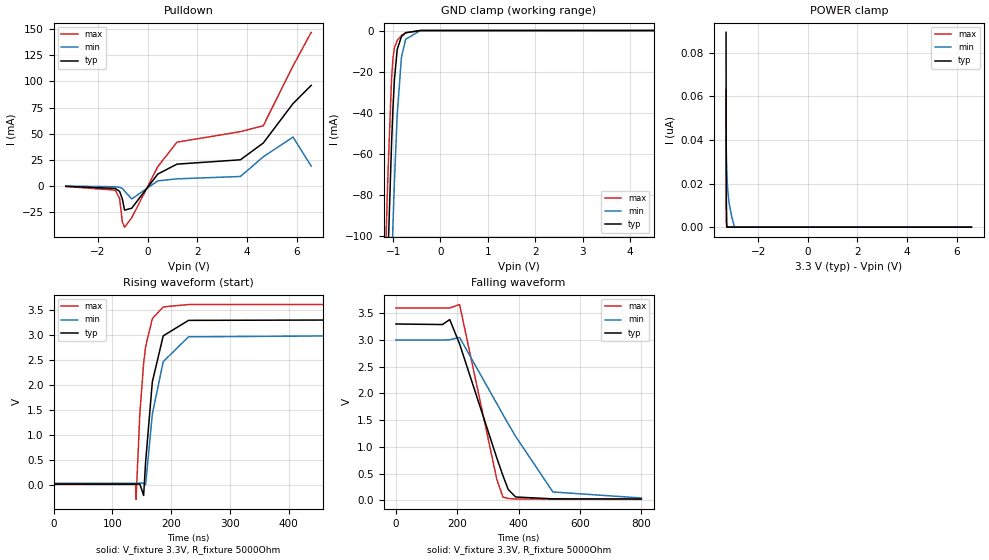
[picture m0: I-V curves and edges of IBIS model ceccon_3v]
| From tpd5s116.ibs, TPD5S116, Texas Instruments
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[Model]   ceccon_3v
Model_type   I/O_open_drain
Polarity   Non-Inverting
Enable   Active-Low
Vinl = .9
Vinh = 2.52
Vmeas = 1.65
Vref = 3.3
Cref = 15pF
Rref = 5000
|   typ   min   max
|   (nom PVT)   (slow PVT)   (fast PVT)
C_comp   0.9944p   0.9335p   1.0791p
| Where nom  PVT is Nominal Process, 3.3V, 27C
|   Fast PVT is Strong Process,  3.6V, -40C
|   Slow PVT is Weak Process,   3.0V, 125C
[Voltage Range]   3.3   3   3.6
[Temperature Range]   27   125   -40
[Pullup Reference]   3.3   3   3.6
[Pulldown Reference]   -0   -0   -0
[Power Clamp Reference]   3.3   3   3.6
[GND Clamp Reference]   -0   -0   -0
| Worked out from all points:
|   slope of the pulldown table from 0 to 0.495 V, typ, clamps not added: 37 ohm
|   GND clamp passes 1 mA (typ) near -0.73 V on its own axis
|   falling waveform, V_fixture 3.3V, R_fixture 5000Ohm: 20-80 % time 112ns typ, 177ns min, 78.7ns max; typ from 3.3 V to 0.024 V
|   rising waveform, V_fixture 3.3V, R_fixture 5000Ohm: 20-80 % time 19.2ns typ, 23.8ns min, 14.4ns max; typ from 0.024 V to 3.3 V
[Pulldown]
|   Voltage   I(typ)   I(min)   I(max)
-3.29V    -264.8uA   -78.16uA   -395.9uA
-1.3V     -2.289mA   -661.8uA   -3.952mA
-1.122V   -5.204mA   -1.276mA   -12.04mA
-1.013V   -12.49mA   -2.369mA   -34.54mA
-924mV    -23.06mA   -4.74mA    -39.32mA
-636.9mV  -21.2mA    -12.36mA   -30.39mA
412.5mV   11.45mA    4.92mA     18.48mA
1.185V    20.94mA    6.875mA    41.96mA
3.739V    25.11mA    9.143mA    51.98mA
4.66V     41.17mA    27.98mA    57.62mA
5.857V    78.84mA    46.85mA    114.9mA
6.59V     96.28mA    19mA       147mA
[GND Clamp]
|   Voltage   I(typ)   I(min)   I(max)
-3.29V    -2.207A    -2.262A    -2.175A
-1.211V   -195mA     -262.1mA   -153.1mA
-1.152V   -144.3mA   -211mA     -102.8mA
-1.112V   -112.1mA   -177.9mA   -71.76mA
-1.033V   -54.92mA   -115.6mA   -23.29mA
-1.003V   -37.74mA   -94.21mA   -13.55mA
-973.5mV  -24.2mA    -74.32mA   -8.55mA
-914.1mV  -9.265mA   -41.02mA   -4.823mA
-825mV    -2.968mA   -13.13mA   -2.43mA
-735.9mV  -1.1mA     -4.271mA   -1.07mA
-429mV    -4.808uA   -22.23uA   -1.788uA
6.59V     0A         0A         0A
[POWER Clamp]
|   Voltage   I(typ)   I(min)   I(max)
-3.29V    89.28nA    41.72nA    63.14nA
-3.28V    12.91nA    34.6nA     2.506nA
-3.27V    6.457nA    29.57nA    1.253nA
-3.26V    0A         25.83nA    0A
-3.241V   0A         20.58nA    0A
-3.221V   0A         17.02nA    0A
-3.191V   0A         13.32nA    0A
-3.161V   0A         10.67nA    0A
-3.053V   0A         4.344nA    0A
-2.954V   0A         161.6pA    0A
-2.934V   0A         0A         0A
6.59V     0A         0A         0A
[Ramp]
R_load = 5000
|   typ   min   max
dV/dt_r   1.96559/1.89851e-08   1.7748/2.38264e-08   2.14933/1.43828e-08
dV/dt_f   1.96557/1.12449e-07   1.77431/1.77199e-07   2.14934/7.86086e-08
[Falling Waveform]
V_fixture = 3.3V
V_fixture_min = 3V
V_fixture_max = 3.6V
R_fixture = 5000Ohm
C_fixture = 0F
|   Time   V(typ)   V(min)   V(max)
0s        3.3V       3V         3.6V
151.8ns   3.29V      3V         3.6V
175.4ns   3.383V     3.005V     3.6V
207.5ns   2.927V     3.049V     3.665V
329ns     789.4mV    1.808V     388mV
348.8ns   462.2mV    1.605V     59.01mV
366ns     202.3mV    1.431V     32.87mV
390.3ns   61.43mV    1.194V     24.86mV
511.7ns   26.79mV    155.9mV    20.48mV
800ns     24.04mV    42.66mV    17.77mV
[Rising Waveform]
V_fixture = 3.3V
V_fixture_min = 3V
V_fixture_max = 3.6V
R_fixture = 5000Ohm
C_fixture = 0F
|   Time   V(typ)   V(min)   V(max)
0s        24mV       41.94mV    17.76mV
139.5ns   24.91mV    42.78mV    18.77mV
140.3ns   24.92mV    42.78mV    -279.1mV
146.8ns   24.96mV    42.82mV    1.437V
153.2ns   -201.8mV   42.86mV    2.428V
156.6ns   469.7mV    14.03mV    2.762V
168ns     2.061V     1.42V      3.319V
186.5ns   2.976V     2.462V     3.552V
229.5ns   3.284V     2.956V     3.599V
800ns     3.3V       3V         3.6V
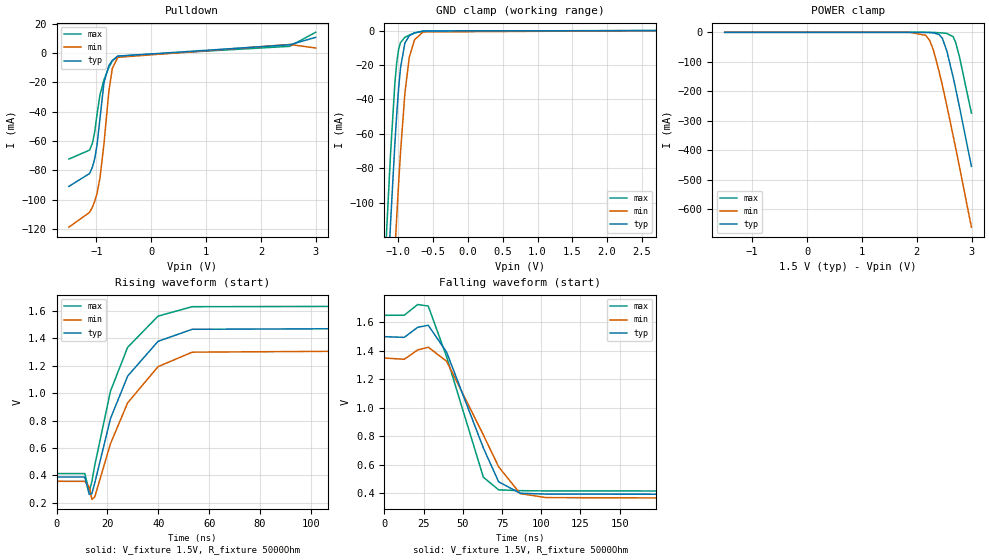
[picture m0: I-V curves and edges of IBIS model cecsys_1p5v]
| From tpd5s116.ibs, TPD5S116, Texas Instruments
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[Model]   cecsys_1p5v
Model_type   I/O_open_drain
Polarity   Non-Inverting
Enable   Active-Low
Vinl = .1107
Vinh = 1.155
Vmeas = 0.75
Vref = 1.5
Cref = 15pF
Rref = 5000
|   typ   min   max
|   (fast PVT)   (slow PVT)   (nom PVT)
C_comp   1.541p   0.9792p   1.562p
| Where nom  PVT is Nominal Process, 1.5V, 27C
|   Fast PVT is Strong Process,  1.65V, -40C
|   Slow PVT is Weak Process,   1.35V, 125C
[Voltage Range]   1.5   1.35   1.65
[Temperature Range]   27   125   -40
[Pullup Reference]   1.5   1.35   1.65
[Pulldown Reference]   -0   -0   -0
[Power Clamp Reference]   1.5   1.35   1.65
[GND Clamp Reference]   -0   -0   -0
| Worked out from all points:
|   slope of the pulldown table from 0 to 0.225 V, typ, clamps not added: 759 ohm
|   GND clamp passes 1 mA (typ) near -0.73 V on its own axis
|   falling waveform, V_fixture 1.5V, R_fixture 5000Ohm: 20-80 % time 23.3ns typ, 26ns min, 20ns max; typ from 1.5 V to 0.388 V
|   rising waveform, V_fixture 1.5V, R_fixture 5000Ohm: 20-80 % time 15.3ns typ, 17.2ns min, 13.4ns max; typ from 0.388 V to 1.5 V
[Pulldown]
|   Voltage   I(typ)   I(min)   I(max)
-1.5V     -90.99mA   -118.8mA   -72.32mA
-1.122V   -82.17mA   -108.7mA   -66.19mA
-1.068V   -77.53mA   -104.9mA   -61.14mA
-1.028V   -71.84mA   -101mA     -53.51mA
-987mV    -62.86mA   -95.73mA   -41.88mA
-933mV    -44.44mA   -85.2mA    -28.38mA
-861mV    -20.3mA    -62.12mA   -18.29mA
-771mV    -8.463mA   -26.03mA   -9.629mA
-708mV    -4.948mA   -10.38mA   -5.408mA
-609mV    -2.069mA   -2.867mA   -2.052mA
2.523V    5.706mA    5.906mA    4.641mA
2.995V    10.77mA    3.528mA    14.2mA
[GND Clamp]
|   Voltage   I(typ)   I(min)   I(max)
-1.5V     -459.6mA   -524.8mA   -419.6mA
-1.167V   -156.8mA   -223.6mA   -115.1mA
-1.113V   -112.4mA   -178.3mA   -71.92mA
-1.05V    -65.57mA   -128mA     -30.5mA
-1.023V   -48.2mA    -107.8mA   -18.38mA
-996mV    -33.32mA   -88.59mA   -10.82mA
-969mV    -21.62mA   -70.73mA   -6.986mA
-906mV    -7.277mA   -36.34mA   -3.927mA
-843mV    -3.002mA   -15.49mA   -2.631mA
-766.5mV  -1.313mA   -5.31mA    -1.448mA
-645mV    -325.3uA   -830.7uA   -306.8uA
2.995V    0A         0A         0A
[POWER Clamp]
|   Voltage   I(typ)   I(min)   I(max)
-1.5V     -130.4pA   -12.09nA   -7.081nA
1.875V    -1.27uA    -105.7uA   -20.84nA
2.163V    -415.8uA   -10.11mA   -18.49uA
2.235V    -955.3uA   -27.78mA   -97.14uA
2.303V    -1.894mA   -60.63mA   -347.8uA
2.406V    -7.277mA   -132.6mA   -1.311mA
2.465V    -20.02mA   -179.5mA   -2.153mA
2.546V    -62.53mA   -248.2mA   -3.671mA
2.663V    -153mA     -352.1mA   -14.91mA
2.708V    -191.6mA   -393.1mA   -34.61mA
2.775V    -251.4mA   -455.2mA   -81.1mA
2.995V    -455.3mA   -661.9mA   -274.3mA
[Ramp]
R_load = 5000
|   typ   min   max
dV/dt_r   0.665673/1.53219e-08   0.595776/1.71867e-08   0.740783/1.33653e-08
dV/dt_f   0.667299/2.32939e-08   0.595601/2.59501e-08   0.742096/1.99555e-08
[Falling Waveform]
V_fixture = 1.5V
V_fixture_min = 1.35V
V_fixture_max = 1.65V
R_fixture = 5000Ohm
C_fixture = 0F
|   Time   V(typ)   V(min)   V(max)
0s        1.5V       1.35V      1.65V
12.67ns   1.495V     1.341V     1.651V
21.2ns    1.566V     1.407V     1.726V
27.95ns   1.58V      1.426V     1.715V
39.65ns   1.391V     1.327V     1.358V
63.07ns   718mV      809.4mV    512.6mV
72.81ns   480.3mV    586.1mV    423.9mV
86.52ns   400.1mV    397.7mV    418.3mV
103.1ns   394.2mV    369.4mV    416.5mV
500ns     387.8mV    357.3mV    413.2mV
[Rising Waveform]
V_fixture = 1.5V
V_fixture_min = 1.35V
V_fixture_max = 1.65V
R_fixture = 5000Ohm
C_fixture = 0F
|   Time   V(typ)   V(min)   V(max)
0s        388.3mV    357.1mV    413.6mV
11.11ns   388.2mV    356.8mV    413.5mV
12.87ns   261mV      315.1mV    282mV
13.89ns   267.1mV    225.4mV    354.7mV
15.03ns   344.9mV    242.6mV    473.6mV
21.2ns    814mV      631mV      1.015V
27.95ns   1.125V     929.6mV    1.335V
39.9ns    1.379V     1.194V     1.563V
53.35ns   1.467V     1.3V       1.632V
500ns     1.498V     1.35V      1.648V
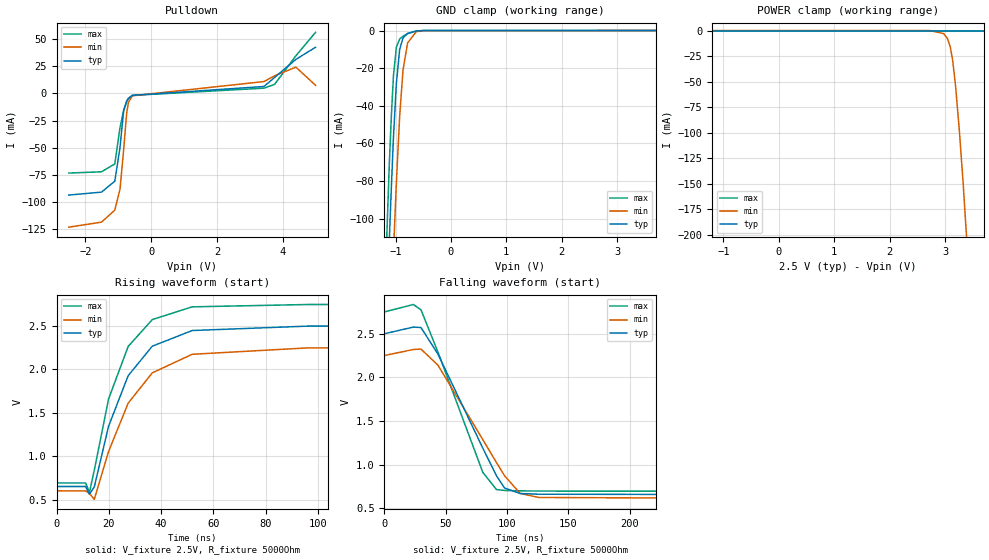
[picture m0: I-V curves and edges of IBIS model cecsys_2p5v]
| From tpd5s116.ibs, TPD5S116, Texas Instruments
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[Model]   cecsys_2p5v
Model_type   I/O_open_drain
Polarity   Non-Inverting
Enable   Active-Low
Vinl = .1845
Vinh = 1.925
Vmeas = 1.25
Vref = 2.5
Cref = 15pF
Rref = 5000
|   typ   min   max
|   (fast PVT)   (slow PVT)   (nom PVT)
C_comp   1.541p   0.9792p   1.562p
| Where nom  PVT is Nominal Process, 2.5V, 27C
|   Fast PVT is Strong Process,  2.75V, -40C
|   Slow PVT is Weak Process,   2.25V, 125C
[Voltage Range]   2.5   2.25   2.75
[Temperature Range]   27   125   -40
[Pullup Reference]   2.5   2.25   2.75
[Pulldown Reference]   -0   -0   -0
[Power Clamp Reference]   2.5   2.25   2.75
[GND Clamp Reference]   -0   -0   -0
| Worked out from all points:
|   slope of the pulldown table from 0 to 0.375 V, typ, clamps not added: 757 ohm
|   GND clamp passes 1 mA (typ) near -0.72 V on its own axis
|   falling waveform, V_fixture 2.5V, R_fixture 5000Ohm: 20-80 % time 37.6ns typ, 41.8ns min, 32.6ns max; typ from 2.5 V to 0.65 V
|   rising waveform, V_fixture 2.5V, R_fixture 5000Ohm: 20-80 % time 14.7ns typ, 16.5ns min, 13ns max; typ from 0.651 V to 2.5 V
[Pulldown]
|   Voltage   I(typ)   I(min)   I(max)
-2.5V     -93.77mA   -123.4mA   -73.47mA
-1.51V    -91.08mA   -118.8mA   -72.34mA
-1.105V   -80.99mA   -107.7mA   -65.06mA
-947.5mV  -50.03mA   -88.55mA   -31.49mA
-835mV    -15.38mA   -51.53mA   -15.7mA
-745mV    -6.991mA   -18.25mA   -7.913mA
-692.5mV  -4.506mA   -8.377mA   -4.856mA
-572.5mV  -1.775mA   -2.19mA    -1.818mA
3.425V    6.38mA     10.94mA    4.835mA
3.748V    14.76mA    16.28mA    8.39mA
4.393V    31.4mA     24.25mA    34.67mA
4.992V    42.57mA    7.465mA    56.37mA
[GND Clamp]
|   Voltage   I(typ)   I(min)   I(max)
-2.5V     -1.429A    -1.487A    -1.394A
-1.255V   -233.5mA   -300.5mA   -191.7mA
-1.113V   -112mA     -177.8mA   -71.55mA
-1.075V   -83.31mA   -147.5mA   -45.22mA
-1.038V   -57.27mA   -118.5mA   -24.34mA
-985mV    -28.13mA   -81.13mA   -8.909mA
-925mV    -9.995mA   -45.44mA   -4.484mA
-865mV    -3.982mA   -21.15mA   -3.033mA
-782.5mV  -1.541mA   -6.617mA   -1.669mA
-625mV    -242.5uA   -591.8uA   -215.1uA
-497.5mV  -22.76uA   -64.94uA   -12.46uA
4.992V    0A         0A         0A
[POWER Clamp]
|   Voltage   I(typ)   I(min)   I(max)
-2.5V     145.4pA    -27.65nA   238.3pA
2.728V    0A         -45.37uA   0A
2.975V    0A         -2.959mA   0A
3.042V    0A         -7.597mA   0A
3.095V    0A         -15.94mA   0A
3.14V     0A         -29.67mA   0A
3.192V    0A         -54.85mA   0A
3.26V     0A         -98.39mA   0A
3.328V    0A         -149.5mA   0A
3.538V    0A         -329.6mA   0A
3.635V    0A         -418.3mA   0A
4.992V    0A         -1.724A    0A
[Ramp]
R_load = 5000
|   typ   min   max
dV/dt_r   1.10831/1.47462e-08   0.989725/1.64857e-08   1.23416/1.29555e-08
dV/dt_f   1.10988/3.75983e-08   0.98947/4.18454e-08   1.23532/3.25926e-08
[Falling Waveform]
V_fixture = 2.5V
V_fixture_min = 2.25V
V_fixture_max = 2.75V
R_fixture = 5000Ohm
C_fixture = 0F
|   Time   V(typ)   V(min)   V(max)
0s        2.5V       2.25V      2.75V
23.61ns   2.576V     2.319V     2.835V
29.76ns   2.571V     2.324V     2.774V
43.58ns   2.267V     2.14V      2.291V
80.17ns   1.188V     1.286V     910.5mV
91.28ns   871.5mV    1.023V     713.2mV
97.97ns   730.4mV    870.2mV    702.7mV
110.6ns   667.9mV    668.7mV    697.8mV
125.9ns   659.6mV    622.2mV    695.8mV
500ns     650.2mV    600.9mV    691.1mV
[Rising Waveform]
V_fixture = 2.5V
V_fixture_min = 2.25V
V_fixture_max = 2.75V
R_fixture = 5000Ohm
C_fixture = 0F
|   Time   V(typ)   V(min)   V(max)
0s        650.6mV    600.5mV    691.5mV
11.11ns   650.5mV    600.2mV    691.4mV
12.58ns   560.9mV    570.5mV    582mV
14.43ns   644.9mV    502.6mV    838.4mV
19.88ns   1.344V     1.053V     1.659V
27.38ns   1.928V     1.611V     2.265V
36.6ns    2.268V     1.961V     2.575V
51.87ns   2.449V     2.175V     2.722V
96.23ns   2.5V       2.249V     2.749V
500ns     2.498V     2.25V      2.748V
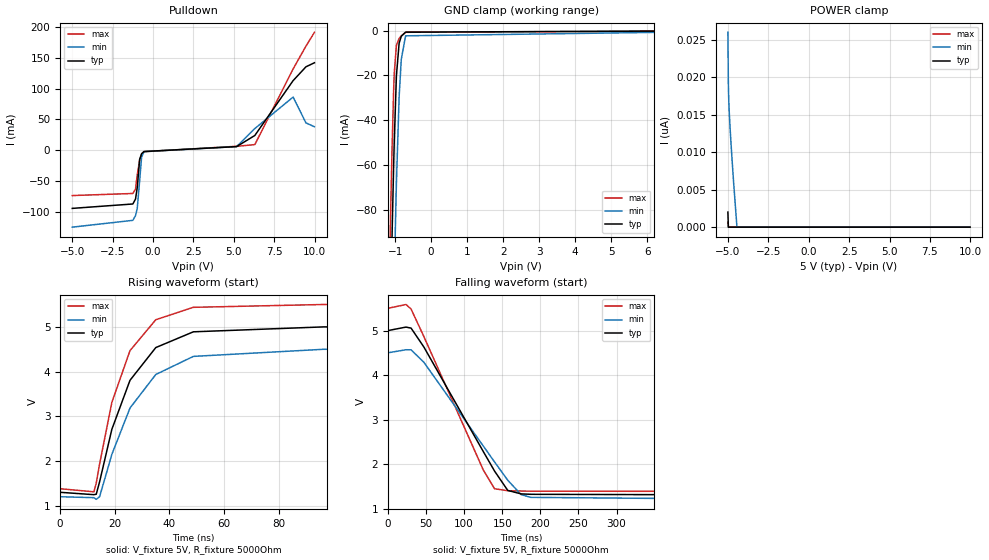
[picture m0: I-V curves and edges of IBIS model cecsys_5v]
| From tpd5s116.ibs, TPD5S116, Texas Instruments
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[Model]   cecsys_5v
Model_type   I/O_open_drain
Polarity   Non-Inverting
Enable   Active-Low
Vinl = .369
Vinh = 3.85
Vmeas = 2.5
Vref = 5
Cref = 15pF
Rref = 5000
|   typ   min   max
|   (fast PVT)   (slow PVT)   (nom PVT)
C_comp   1.541p   0.9792p   1.562p
| Where nom  PVT is Nominal Process, 5V, 27C
|   Fast PVT is Strong Process,  5.5V, -40C
|   Slow PVT is Weak Process,   4.5V, 125C
[Voltage Range]   5   4.5   5.5
[Temperature Range]   27   125   -40
[Pullup Reference]   5   4.5   5.5
[Pulldown Reference]   -0   -0   -0
[Power Clamp Reference]   5   4.5   5.5
[GND Clamp Reference]   -0   -0   -0
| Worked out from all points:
|   slope of the pulldown table from 0 to 0.75 V, typ, clamps not added: 756 ohm
|   GND clamp passes 1 mA (typ) near -0.74 V on its own axis
|   falling waveform, V_fixture 5V, R_fixture 5000Ohm: 20-80 % time 73.5ns typ, 81.5ns min, 64ns max; typ from 5 V to 1.3 V
|   rising waveform, V_fixture 5V, R_fixture 5000Ohm: 20-80 % time 14.1ns typ, 15.7ns min, 12.3ns max; typ from 1.3 V to 5 V
[Pulldown]
|   Voltage   I(typ)   I(min)   I(max)
-5V       -94.67mA   -125.2mA   -73.79mA
-1.25V    -87.49mA   -114.1mA   -70.4mA
-1.085V   -79.38mA   -106.4mA   -63.37mA
-980mV    -61.07mA   -94.73mA   -40.27mA
-830mV    -15.03mA   -49.59mA   -15.72mA
-710mV    -5.7mA     -11.18mA   -6.309mA
-560mV    -2.146mA   -2.399mA   -2.307mA
5.17V     5.86mA     5.915mA    6.36mA
6.295V    23.96mA    35.2mA     9.088mA
8.665V    113.2mA    86.45mA    132.2mA
9.46V     135.7mA    44.45mA    169.4mA
9.985V    142.3mA    38.17mA    191.8mA
[GND Clamp]
|   Voltage   I(typ)   I(min)   I(max)
-5V       -3.901A    -3.952A    -3.873A
-1.19V    -176.4mA   -243.4mA   -134.5mA
-1.145V   -138.4mA   -204.9mA   -96.96mA
-1.115V   -114mA     -179.9mA   -73.43mA
-1.085V   -90.75mA   -155.5mA   -51.82mA
-1.04V    -58.89mA   -120.4mA   -25.5mA
-1.025V   -49.41mA   -109.2mA   -19.12mA
-965mV    -20.19mA   -68.22mA   -6.626mA
-890mV    -5.675mA   -29.67mA   -3.546mA
-830mV    -2.57mA    -12.87mA   -2.407mA
-710mV    -732uA     -2.368mA   -792uA
9.985V    0A         0A         0A
[POWER Clamp]
|   Voltage   I(typ)   I(min)   I(max)
-5V       2.008nA    25.96nA    651pA
-4.97V    0A         19.13nA    0A
-4.955V   0A         17.63nA    0A
-4.94V    0A         16.6nA     0A
-4.91V    0A         15.09nA    0A
-4.865V   0A         13.27nA    0A
-4.805V   0A         11.12nA    0A
-4.73V    0A         8.626nA    0A
-4.64V    0A         5.805nA    0A
-4.445V   0A         176.5pA    0A
-4.415V   0A         0A         0A
9.985V    0A         0A         0A
[Ramp]
R_load = 5000
|   typ   min   max
dV/dt_r   2.21633/1.41414e-08   1.97642/1.57e-08   2.46795/1.23429e-08
dV/dt_f   2.21729/7.35108e-08   1.97607/8.14999e-08   2.46875/6.40192e-08
[Falling Waveform]
V_fixture = 5V
V_fixture_min = 4.5V
V_fixture_max = 5.5V
R_fixture = 5000Ohm
C_fixture = 0F
|   Time   V(typ)   V(min)   V(max)
0s        5V         4.5V       5.5V
23.61ns   5.078V     4.569V     5.586V
30.3ns    5.056V     4.568V     5.485V
47.11ns   4.631V     4.288V     4.866V
125.1ns   2.281V     2.405V     1.867V
139.9ns   1.842V     2.047V     1.445V
157.2ns   1.407V     1.636V     1.4V
174.8ns   1.329V     1.313V     1.394V
187.4ns   1.32V      1.251V     1.39V
500ns     1.305V     1.207V     1.385V
[Rising Waveform]
V_fixture = 5V
V_fixture_min = 4.5V
V_fixture_max = 5.5V
R_fixture = 5000Ohm
C_fixture = 0F
|   Time   V(typ)   V(min)   V(max)
0s        1.305V     1.206V     1.385V
12.38ns   1.252V     1.185V     1.316V
13.22ns   1.262V     1.148V     1.51V
14.45ns   1.54V      1.207V     1.939V
18.93ns   2.71V      2.151V     3.312V
25.58ns   3.806V     3.187V     4.469V
35.03ns   4.537V     3.936V     5.159V
48.79ns   4.889V     4.34V      5.436V
96.51ns   4.999V     4.499V     5.499V
500ns     4.998V     4.5V       5.499V
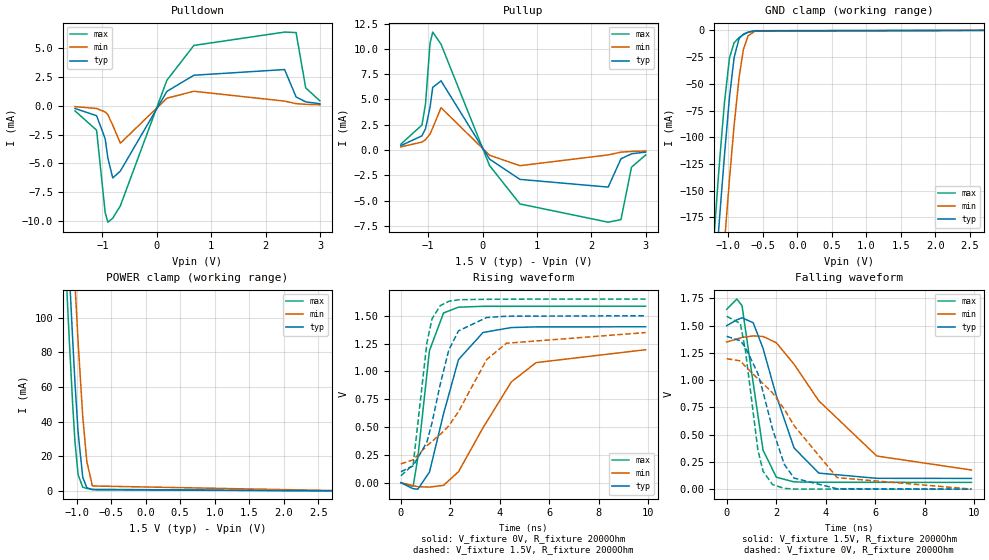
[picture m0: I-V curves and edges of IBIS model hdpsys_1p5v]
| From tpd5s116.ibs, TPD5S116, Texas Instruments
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[Model]   hdpsys_1p5v
Model_type   3-state
Polarity   Non-Inverting
Vmeas = 0.75
Vref = 1.5
Cref = 15pF
Rref = 2000
|   typ   min   max
|   (nom PVT)   (slow PVT)   (fast PVT)
C_comp   1.1241p   1.0342p   1.3025p
|C_comp (High state)   1.1241p   1.0342p   1.3025p
|C_comp (Low state)   1.0197p   0.970p   1.0858p
| Where nom  PVT is Nominal Process, 1.5V, 27C
|   Fast PVT is Strong Process,  1.65V, -40C
|   Slow PVT is Weak Process,   1.35V, 125C
[Voltage Range]   1.5   1.35   1.65
[Temperature Range]   27   125   -40
[Pullup Reference]   1.5   1.35   1.65
[Pulldown Reference]   -0   -0   -0
[Power Clamp Reference]   1.5   1.35   1.65
[GND Clamp Reference]   -0   -0   -0
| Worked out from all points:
|   slope of the pulldown table from 0 to 0.225 V, typ, clamps not added: 158 ohm
|   slope of the pullup table from 0 to 0.225 V, typ, clamps not added: 155 ohm
|   GND clamp passes 1 mA (typ) near -0.66 V on its own axis
|   POWER clamp passes 1 mA (typ) near -0.80 V on its own axis
|   falling waveform, V_fixture 1.5V, R_fixture 2000Ohm: 20-80 % time 1.16ns typ, 2.49ns min, 576ps max; typ from 1.5 V to 0.098 V
|   rising waveform, V_fixture 0V, R_fixture 2000Ohm: 20-80 % time 980ps typ, 1.96ns min, 495ps max; typ from 0 V to 1.4 V
|   rising waveform, V_fixture 1.5V, R_fixture 2000Ohm: 20-80 % time 916ps typ, 2.06ns min, 468ps max; typ from 0.098 V to 1.5 V
|   falling waveform, V_fixture 0V, R_fixture 2000Ohm: 20-80 % time 1.06ns typ, 2.18ns min, 542ps max; typ from 1.4 V to 0 V
[Pulldown]
|   Voltage   I(typ)   I(min)   I(max)
-1.5V     -248.1uA   -88.02uA   -457.5uA
-1.104V   -871.1uA   -247.2uA   -2.122mA
-946.5mV  -2.863mA   -549.3uA   -9.232mA
-897mV    -4.526mA   -783.3uA   -10.07mA
-807mV    -6.252mA   -1.702mA   -9.723mA
-667.5mV  -5.652mA   -3.248mA   -8.654mA
187.5mV   1.233mA    640.6uA    2.198mA
682.5mV   2.623mA    1.239mA    5.199mA
2.348V    3.115mA    388uA      6.351mA
2.559V    751.6uA    167.7uA    6.309mA
2.735V    323.1uA    110.7uA    1.533mA
2.995V    167.8uA    72.76uA    415.7uA
[GND Clamp]
|   Voltage   I(typ)   I(min)   I(max)
-1.5V     -519.3mA   -603.1mA   -466.8mA
-1.252V   -288.2mA   -373.1mA   -234.6mA
-1.145V   -191.7mA   -276.1mA   -138.7mA
-1.113V   -164.6mA   -248.5mA   -112.3mA
-1.054V   -116.2mA   -198.3mA   -67.04mA
-982.5mV  -62.69mA   -139.3mA   -25.86mA
-915mV    -25.32mA   -88.77mA   -11.53mA
-843mV    -7.655mA   -43.85mA   -6.807mA
-780mV    -3.531mA   -17.62mA   -4.03mA
-712.5mV  -1.697mA   -5.112mA   -1.888mA
-613.5mV  -423.1uA   -871.9uA   -359.4uA
2.995V    0A         0A         0A
[Pullup]
|   Voltage   I(typ)   I(min)   I(max)
-1.5V     435.4uA    314.9uA    578.6uA
-1.113V   1.403mA    785.8uA    2.473mA
-1.046V   2.129mA    1.034mA    4.621mA
-964.5mV  4.216mA    1.582mA    10.54mA
-915mV    6.194mA    2.174mA    11.66mA
-762mV    6.839mA    4.188mA    10.46mA
129mV     -897.5uA   -515.4uA   -1.538mA
687mV     -2.9mA     -1.545mA   -5.329mA
2.307V    -3.663mA   -480.7uA   -7.132mA
2.541V    -868.4uA   -208.6uA   -6.877mA
2.735V    -370.7uA   -138.3uA   -1.695mA
2.995V    -201.2uA   -94.21uA   -488.4uA
[POWER Clamp]
|   Voltage   I(typ)   I(min)   I(max)
-1.5V     485.2mA    543.9mA    447.6mA
-1.27V    271mA      331.6mA    231.5mA
-1.149V   162.9mA    223.7mA    123mA
-1.122V   139.9mA    200.5mA    100.3mA
-1.099V   121.1mA    181.5mA    81.95mA
-1.054V   85.39mA    144.4mA    48.15mA
-1.023V   62.28mA    119.5mA    28.21mA
-978mV    33.74mA    85.98mA    9.328mA
-910.5mV  7.797mA    42.85mA    2.157mA
-852mV    1.863mA    17.04mA    1.423mA
-771mV    684.4uA    2.864mA    911.5uA
2.995V    0A         0A         0A
[Ramp]
R_load = 2000
|   typ   min   max
dV/dt_r   0.840813/9.80062e-10   0.716776/1.9599e-09   0.951748/4.95326e-10
dV/dt_f   0.840911/1.15757e-09   0.704594/2.48756e-09   0.952672/5.7585e-10
[Falling Waveform]
V_fixture = 1.5V
V_fixture_min = 1.35V
V_fixture_max = 1.65V
R_fixture = 2000Ohm
C_fixture = 0F
|   Time   V(typ)   V(min)   V(max)
0s        1.5V       1.35V      1.65V
409.8ps   1.553V     1.377V     1.744V
620.7ps   1.572V     1.392V     1.684V
1.072ns   1.527V     1.406V     972.6mV
1.471ns   1.291V     1.401V     357.5mV
2.008ns   855.6mV    1.343V     110mV
2.725ns   377.9mV    1.146V     66.33mV
3.725ns   147.4mV    810.5mV    63.16mV
6.068ns   99.49mV    304.1mV    62.8mV
9.9ns     98.48mV    175.7mV    62.21mV
[Rising Waveform]
V_fixture = 0V
V_fixture_min = 0V
V_fixture_max = 0V
R_fixture = 2000Ohm
C_fixture = 0F
|   Time   V(typ)   V(min)   V(max)
0s        4.152nV    229.4nV    1.211nV
498.7ps   -54.33mV   -27.65mV   -32.21mV
688.8ps   -58.07mV   -35.93mV   229.9mV
1.157ns   95.43mV    -39.63mV   1.187V
1.726ns   618.2mV    -23.72mV   1.525V
2.33ns    1.106V     98.5mV     1.577V
3.325ns   1.35V      494.8mV    1.585V
4.468ns   1.394V     905.7mV    1.585V
5.468ns   1.4V       1.079V     1.585V
9.9ns     1.401V     1.195V     1.586V
[Rising Waveform]
V_fixture = 1.5V
V_fixture_min = 1.35V
V_fixture_max = 1.65V
R_fixture = 2000Ohm
C_fixture = 0F
|   Time   V(typ)   V(min)   V(max)
0s        98.33mV    169.2mV    62.21mV
498.7ps   152mV      205.8mV    161.1mV
1.053ns   365mV      331.9mV    1.256V
1.262ns   540.4mV    371.6mV    1.474V
1.598ns   889.4mV    435mV      1.592V
1.939ns   1.192V     511.5mV    1.63V
2.33ns    1.364V     638.3mV    1.644V
3.468ns   1.484V     1.106V     1.648V
4.268ns   1.496V     1.253V     1.649V
9.9ns     1.5V       1.349V     1.65V
[Falling Waveform]
|Gnd
V_fixture = 0V
V_fixture_min = 0V
V_fixture_max = 0V
R_fixture = 2000Ohm
C_fixture = 0F
|   Time   V(typ)   V(min)   V(max)
0s        1.402V     1.197V     1.586V
552.5ps   1.362V     1.177V     1.52V
756.9ps   1.301V     1.125V     1.271V
1.262ns   1.061V     1.013V     359.8mV
1.471ns   891.8mV    969.1mV    164.9mV
1.853ns   551.9mV    883.7mV    41.87mV
2.33ns    227.4mV    735mV      7.179mV
2.725ns   101.6mV    583.2mV    1.31mV
4.468ns   3.193mV    105.6mV    413.2uV
9.9ns     121.4uV    676.3uV    5.388uV
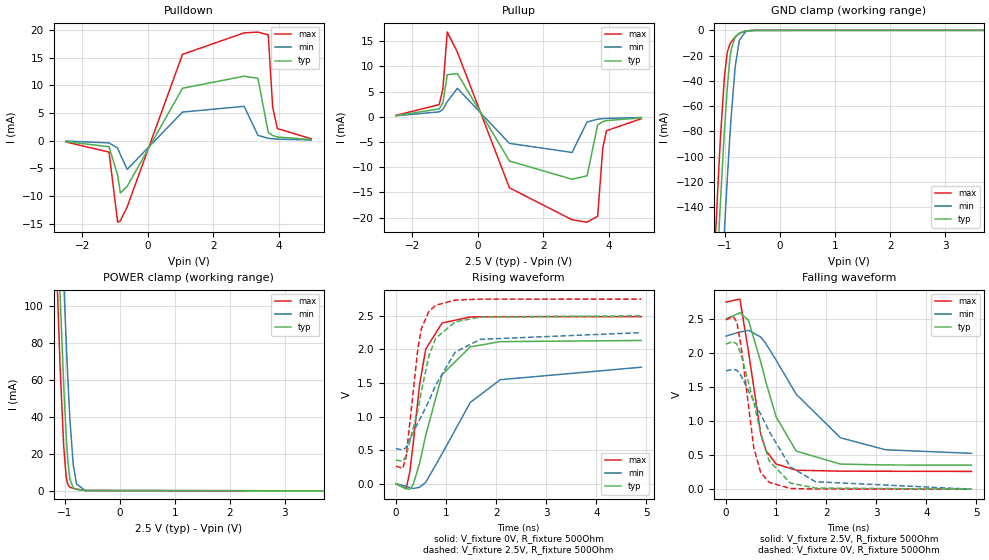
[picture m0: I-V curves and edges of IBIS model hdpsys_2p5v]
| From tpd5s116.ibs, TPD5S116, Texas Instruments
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[Model]   hdpsys_2p5v
Model_type   3-state
Polarity   Non-Inverting
Vmeas = 1.25
Vref = 2.5
Cref = 15pF
Rref = 500
|   typ   min   max
|   (nom PVT)   (slow PVT)   (fast PVT)
C_comp   1.1241p   1.0342p   1.3025p
|C_comp (High state)   1.1241p   1.0342p   1.3025p
|C_comp (Low state)   1.0197p   0.970p   1.0858p
| Where nom  PVT is Nominal Process, 2.5V, 27C
|   Fast PVT is Strong Process,  2.75V, -40C
|   Slow PVT is Weak Process,   2.25V, 125C
[Voltage Range]   2.5   2.25   2.75
[Temperature Range]   27   125   -40
[Pullup Reference]   2.5   2.25   2.75
[Pulldown Reference]   -0   -0   -0
[Power Clamp Reference]   2.5   2.25   2.75
[GND Clamp Reference]   -0   -0   -0
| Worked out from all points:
|   slope of the pulldown table from 0 to 0.375 V, typ, clamps not added: 83.1 ohm
|   slope of the pullup table from 0 to 0.375 V, typ, clamps not added: 86.6 ohm
|   GND clamp passes 1 mA (typ) near -0.66 V on its own axis
|   POWER clamp passes 1 mA (typ) near -0.80 V on its own axis
|   falling waveform, V_fixture 2.5V, R_fixture 500Ohm: 20-80 % time 543ps typ, 1.03ns min, 306ps max; typ from 2.5 V to 0.354 V
|   rising waveform, V_fixture 0V, R_fixture 500Ohm: 20-80 % time 467ps typ, 861ps min, 260ps max; typ from 0 V to 2.13 V
|   rising waveform, V_fixture 2.5V, R_fixture 500Ohm: 20-80 % time 383ps typ, 707ps min, 224ps max; typ from 0.354 V to 2.5 V
|   falling waveform, V_fixture 0V, R_fixture 500Ohm: 20-80 % time 443ps typ, 780ps min, 264ps max; typ from 2.13 V to 0 V
[Pulldown]
|   Voltage   I(typ)   I(min)   I(max)
-2.5V     -154.4uA   -63.6uA    -229.3uA
-1.18V    -1.092mA   -399.9uA   -2.061mA
-917.5mV  -6.227mA   -1.337mA   -14.73mA
-835mV    -9.463mA   -2.5mA     -14.48mA
-625mV    -8.229mA   -5.183mA   -11.94mA
1.062V    9.473mA    5.173mA    15.6mA
2.945V    11.66mA    6.213mA    19.49mA
3.365V    11.27mA    970.3uA    19.63mA
3.68V     1.478mA    430.5uA    19.12mA
3.815V    934.8uA    344.8uA    6.065mA
3.958V    666.9uA    284.3uA    2.196mA
4.992V    210.9uA    123.6uA    341.3uA
[GND Clamp]
|   Voltage   I(typ)   I(min)   I(max)
-2.5V     -1.49A     -1.569A    -1.443A
-1.232V   -270mA     -354.9mA   -216.4mA
-1.083V   -138.9mA   -222.1mA   -87.93mA
-1.008V   -80.17mA   -159.4mA   -37.36mA
-955mV    -45.4mA    -118mA     -17.52mA
-910mV    -23.32mA   -85.28mA   -11.06mA
-887.5mV  -15.89mA   -70.19mA   -9.344mA
-812.5mV  -5.091mA   -29.31mA   -5.37mA
-737.5mV  -2.248mA   -8.203mA   -2.576mA
-625mV    -510.5uA   -1.059mA   -451.6uA
-475mV    -27.4uA    -82uA      -13.34uA
4.992V    0A         0A         0A
[Pullup]
|   Voltage   I(typ)   I(min)   I(max)
-2.5V     227.6uA    185.1uA    275.6uA
-1.18V    1.549mA    966.7uA    2.408mA
-1.067V   2.77mA     1.444mA    5.521mA
-932.5mV  8.335mA    2.979mA    16.8mA
-625mV    8.58mA     5.649mA    12.83mA
965mV     -8.779mA   -5.286mA   -14.11mA
2.877V    -12.41mA   -7.088mA   -20.45mA
3.335V    -11.72mA   -1.049mA   -20.93mA
3.658V    -1.624mA   -487uA     -19.74mA
3.815V    -979.5uA   -382.7uA   -6.185mA
3.928V    -757.2uA   -331.5uA   -2.776mA
4.992V    -234.2uA   -144.5uA   -381.9uA
[POWER Clamp]
|   Voltage   I(typ)   I(min)   I(max)
-2.5V     1.457A     1.509A     1.424A
-1.232V   236.6mA    297.4mA    196.8mA
-1.083V   107.3mA    167.3mA    68.65mA
-1.075V   101.4mA    161.1mA    62.97mA
-1.015V   56.76mA    113.4mA    23.89mA
-970mV    29.45mA    80.34mA    7.436mA
-940mV    16.12mA    60.35mA    3.451mA
-902.5mV  6.315mA    38.56mA    1.986mA
-842.5mV  1.561mA    14.17mA    1.354mA
-782.5mV  753.4uA    3.744mA    976.9uA
-625mV    178.8uA    200.2uA    254.2uA
4.992V    0A         0A         0A
[Ramp]
R_load = 500
|   typ   min   max
dV/dt_r   1.27952/4.66622e-10   1.04123/8.61178e-10   1.49285/2.59868e-10
dV/dt_f   1.28763/5.43343e-10   1.03411/1.03487e-09   1.49353/3.06488e-10
[Falling Waveform]
V_fixture = 2.5V
V_fixture_min = 2.25V
V_fixture_max = 2.75V
R_fixture = 500Ohm
C_fixture = 0F
|   Time   V(typ)   V(min)   V(max)
0s        2.5V       2.25V      2.75V
276.4ps   2.593V     2.311V     2.794V
447.4ps   2.483V     2.334V     2.024V
691.3ps   1.874V     2.236V     816.7mV
795.9ps   1.573V     2.139V     569mV
999ps     1.064V     1.897V     370.2mV
1.401ns   559mV      1.395V     278.4mV
2.284ns   368.7mV    755.4mV    264.7mV
3.185ns   355.5mV    579.1mV    263.4mV
4.9ns     353.9mV    526.5mV    260.8mV
[Rising Waveform]
V_fixture = 0V
V_fixture_min = 0V
V_fixture_max = 0V
R_fixture = 500Ohm
C_fixture = 0F
|   Time   V(typ)   V(min)   V(max)
0s        3.994nV    164.1nV    1.252nV
202.5ps   -76.16mV   -37.65mV   -77.3mV
276.4ps   -81.4mV    -59.83mV   171.6mV
347.2ps   -7.36mV    -71.43mV   611.3mV
473.3ps   305.9mV    -52.75mV   1.482V
595.7ps   724.2mV    20.77mV    2.007V
922.7ps   1.625V     447.2mV    2.394V
1.484ns   2.038V     1.21V      2.483V
2.084ns   2.116V     1.549V     2.488V
4.9ns     2.133V     1.735V     2.488V
[Rising Waveform]
V_fixture = 2.5V
V_fixture_min = 2.25V
V_fixture_max = 2.75V
R_fixture = 500Ohm
C_fixture = 0F
|   Time   V(typ)   V(min)   V(max)
0s        353.7mV    522.2mV    260.7mV
136.6ps   332mV      503.6mV    228.9mV
202.5ps   412.6mV    539.4mV    393mV
437.5ps   1.093V     905.4mV    2.007V
509.1ps   1.38V      1.005V     2.312V
659.5ps   1.909V     1.234V     2.568V
795.9ps   2.169V     1.472V     2.658V
1.184ns   2.41V      1.959V     2.735V
1.684ns   2.482V     2.15V      2.749V
4.9ns     2.5V       2.25V      2.75V
[Falling Waveform]
|Gnd
V_fixture = 0V
V_fixture_min = 0V
V_fixture_max = 0V
R_fixture = 500Ohm
C_fixture = 0F
|   Time   V(typ)   V(min)   V(max)
0s        2.133V     1.738V     2.488V
136.6ps   2.169V     1.763V     2.541V
215.5ps   2.134V     1.749V     2.458V
300.8ps   1.976V     1.666V     2.097V
552.4ps   1.28V      1.292V     611.5mV
691.3ps   824.3mV    1.103V     247.2mV
859.3ps   417.5mV    852.3mV    100.4mV
1.284ns   90.08mV    327.6mV    9.848mV
1.784ns   16.8mV     109mV      2.428mV
4.9ns     177.7uV    519.1uV    39.49uV
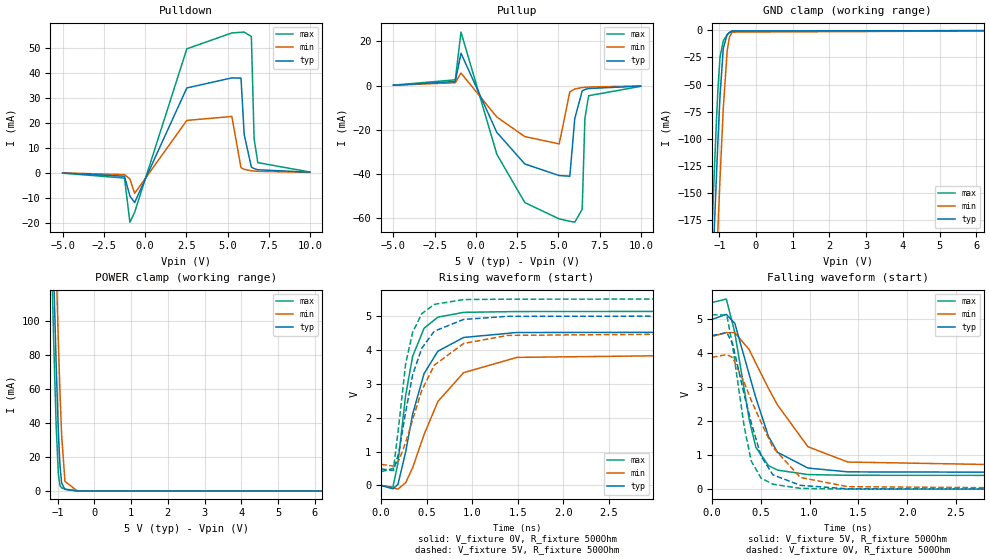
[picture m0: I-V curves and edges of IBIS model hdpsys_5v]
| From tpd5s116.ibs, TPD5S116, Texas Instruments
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[Model]   hdpsys_5v
Model_type   3-state
Polarity   Non-Inverting
Vmeas = 2.5
Vref = 5
Cref = 15pF
Rref = 500
|   typ   min   max
|   (nom PVT)   (slow PVT)   (fast PVT)
C_comp   1.1241p   1.0342p   1.3025p
|C_comp (High state)   1.1241p   1.0342p   1.3025p
|C_comp (Low state)   1.0197p   0.970p   1.0858p
| Where nom  PVT is Nominal Process, 5V, 27C
|   Fast PVT is Strong Process,  5.5V, -40C
|   Slow PVT is Weak Process,   4.5V, 125C
[Voltage Range]   5   4.5   5.5
[Temperature Range]   27   125   -40
[Pullup Reference]   5   4.5   5.5
[Pulldown Reference]   -0   -0   -0
[Power Clamp Reference]   5   4.5   5.5
[GND Clamp Reference]   -0   -0   -0
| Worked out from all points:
|   slope of the pulldown table from 0 to 0.75 V, typ, clamps not added: 55.5 ohm
|   slope of the pullup table from 0 to 0.75 V, typ, clamps not added: 55 ohm
|   GND clamp passes 1 mA (typ) near -0.67 V on its own axis
|   POWER clamp passes 1 mA (typ) near -0.81 V on its own axis
|   falling waveform, V_fixture 5V, R_fixture 500Ohm: 20-80 % time 289ps typ, 481ps min, 189ps max; typ from 5 V to 0.486 V
|   rising waveform, V_fixture 0V, R_fixture 500Ohm: 20-80 % time 267ps typ, 420ps min, 178ps max; typ from 0 V to 4.52 V
|   rising waveform, V_fixture 5V, R_fixture 500Ohm: 20-80 % time 234ps typ, 352ps min, 161ps max; typ from 0.486 V to 5 V
|   falling waveform, V_fixture 0V, R_fixture 500Ohm: 20-80 % time 249ps typ, 387ps min, 168ps max; typ from 4.52 V to 0 V
[Pulldown]
|   Voltage   I(typ)   I(min)   I(max)
-5V       -94.62uA   -53.41uA   -118.5uA
-1.25V    -1.36mA    -684.8uA   -2.105mA
-920mV    -9.275mA   -2.481mA   -19.72mA
-635mV    -11.88mA   -8.206mA   -15.78mA
2.53V     33.89mA    20.93mA    49.51mA
5.26V     37.91mA    22.5mA     55.86mA
5.815V    37.83mA    2.055mA    56.12mA
6.01V     15.21mA    1.409mA    56.2mA
6.445V    2.269mA    819.1uA    54.42mA
6.61V     1.673mA    705.5uA    13.59mA
6.835V    1.227mA    592.9uA    4.068mA
9.985V    254.5uA    181.5uA    339.4uA
[GND Clamp]
|   Voltage   I(typ)   I(min)   I(max)
-5V       -3.964A    -4.035A    -3.921A
-1.25V    -285.9mA   -370.8mA   -232.3mA
-1.16V    -205.3mA   -289.8mA   -152.1mA
-1.13V    -179.1mA   -263.3mA   -126.4mA
-1.07V    -128.7mA   -211.4mA   -78.39mA
-1.04V    -104.7mA   -186.1mA   -57.01mA
-980mV    -61.03mA   -137.4mA   -24.91mA
-890mV    -16.6mA    -71.81mA   -9.513mA
-785mV    -3.726mA   -19.15mA   -4.223mA
-725mV    -1.958mA   -6.479mA   -2.216mA
-650mV    -749.1uA   -1.627mA   -719.3uA
9.985V    0A         0A         0A
[Pullup]
|   Voltage   I(typ)   I(min)   I(max)
-5V       129.9uA    114.4uA    149.3uA
-1.25V    1.812mA    1.251mA    2.571mA
-905mV    14.59mA    5.643mA    24.12mA
1.27V     -21.18mA   -14.26mA   -31.07mA
2.965V    -35.43mA   -23.05mA   -52.87mA
5.05V     -40.66mA   -26.37mA   -60.23mA
5.695V    -40.97mA   -2.843mA   -61.31mA
5.995V    -14.93mA   -1.567mA   -61.72mA
6.445V    -2.445mA   -922.6uA   -55.85mA
6.61V     -1.828mA   -800.4uA   -14.74mA
6.835V    -1.355mA   -677.4uA   -4.613mA
9.985V    -287.5uA   -212.9uA   -387.9uA
[POWER Clamp]
|   Voltage   I(typ)   I(min)   I(max)
-5V       3.931A     3.975A     3.904A
-1.19V    198.6mA    259.6mA    158.8mA
-1.145V   159.4mA    220.3mA    119.6mA
-1.115V   134mA      194.6mA    94.49mA
-1.1V     121.6mA    181.9mA    82.35mA
-1.04V    74.51mA    132.8mA    38.46mA
-980mV    34.86mA    87.41mA    9.869mA
-935mV    14.37mA    57.21mA    3.118mA
-890mV    4.541mA    32.3mA     1.789mA
-800mV    886.2uA    5.626mA    1.08mA
-470mV    11.05uA    19.6uA     10.56uA
9.985V    0A         0A         0A
[Ramp]
R_load = 500
|   typ   min   max
dV/dt_r   2.71434/2.66833e-10   2.33017/4.20457e-10   3.0826/1.782e-10
dV/dt_f   2.70838/2.89311e-10   2.32677/4.80283e-10   3.05714/1.88969e-10
[Falling Waveform]
V_fixture = 5V
V_fixture_min = 4.5V
V_fixture_max = 5.5V
R_fixture = 500Ohm
C_fixture = 0F
|   Time   V(typ)   V(min)   V(max)
0s        5V         4.5V       5.5V
147.4ps   5.151V     4.612V     5.601V
234.2ps   4.888V     4.614V     4.618V
382.1ps   3.375V     4.11V      2.054V
449.4ps   2.698V     3.714V     1.238V
578.2ps   1.563V     2.975V     697.1mV
672.1ps   1.085V     2.48V      561.4mV
983.4ps   622.7mV    1.25V      430.7mV
1.392ns   509.6mV    799.1mV    408.6mV
4.9ns     486mV      622.1mV    404.8mV
[Rising Waveform]
V_fixture = 0V
V_fixture_min = 0V
V_fixture_max = 0V
R_fixture = 500Ohm
C_fixture = 0F
|   Time   V(typ)   V(min)   V(max)
0s        10.99nV    318.7nV    2.263nV
129.2ps   -97.58mV   -67.95mV   -54.21mV
184.8ps   28.49mV    -109.3mV   652.3mV
269.2ps   983.3mV    80.8mV     2.654V
346ps     2.104V     520.2mV    3.808V
471.7ps   3.301V     1.502V     4.638V
623.3ps   3.962V     2.478V     4.966V
906.1ps   4.367V     3.329V     5.108V
1.492ns   4.514V     3.779V     5.132V
4.9ns     4.524V     3.884V     5.138V
[Rising Waveform]
V_fixture = 5V
V_fixture_min = 4.5V
V_fixture_max = 5.5V
R_fixture = 500Ohm
C_fixture = 0F
|   Time   V(typ)   V(min)   V(max)
0s        485.7mV    621.5mV    404.6mV
136.9ps   442.5mV    571.2mV    507.5mV
193.1ps   954.6mV    727mV      1.746V
269.2ps   2.159V     1.263V     3.588V
346ps     3.261V     1.938V     4.517V
446.5ps   4.049V     2.806V     5.07V
584.5ps   4.554V     3.551V     5.344V
906.1ps   4.899V     4.19V      5.485V
1.392ns   4.991V     4.429V     5.497V
4.9ns     5V         4.5V       5.5V
[Falling Waveform]
|Gnd
V_fixture = 0V
V_fixture_min = 0V
V_fixture_max = 0V
R_fixture = 500Ohm
C_fixture = 0F
|   Time   V(typ)   V(min)   V(max)
0s        4.524V     3.884V     5.138V
152.7ps   4.612V     3.967V     5.131V
211.5ps   4.288V     3.877V     4.218V
330.7ps   2.786V     3.143V     1.846V
402.8ps   1.958V     2.62V      829.3mV
502.7ps   981.9mV    1.976V     329.1mV
623.3ps   423.4mV    1.235V     146.9mV
906.1ps   112.7mV    345mV      23.12mV
1.392ns   9.991mV    73.19mV    1.902mV
4.9ns     230.5uV    384.7uV    48.32uV
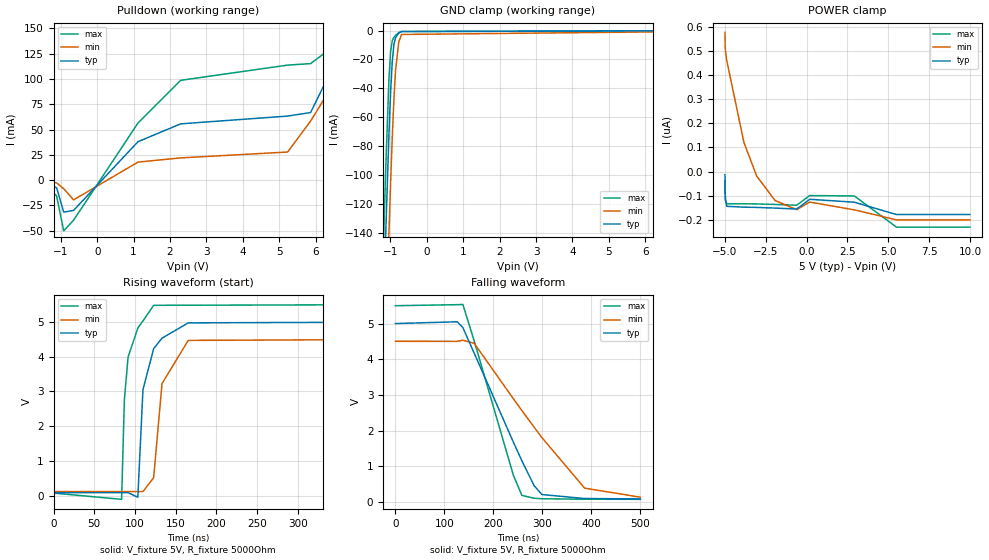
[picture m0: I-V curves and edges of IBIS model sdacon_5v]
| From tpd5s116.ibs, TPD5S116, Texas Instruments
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[Model]   sdacon_5v
Model_type   I/O_open_drain
Polarity   Non-Inverting
Enable   Active-Low
Vinl = 1.35
Vinh = 3.85
Vmeas = 2.5
Vref = 5
Cref = 15pF
Rref = 5000
|   typ   min   max
|   (nom PVT)   (slow PVT)   (fast PVT)
C_comp   2.077p   1.340p   2.152p
| Where nom  PVT is Nominal Process, 5V, 27C
|   Fast PVT is Strong Process,  5.5V, -40C
|   Slow PVT is Weak Process,   4.5V, 125C
[Voltage Range]   5   4.5   5.5
[Temperature Range]   27   125   -40
[Pullup Reference]   5   4.5   5.5
[Pulldown Reference]   -0   -0   -0
[Power Clamp Reference]   5   4.5   5.5
[GND Clamp Reference]   -0   -0   -0
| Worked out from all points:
|   slope of the pulldown table from 0 to 0.75 V, typ, clamps not added: 25.8 ohm
|   GND clamp passes 1 mA (typ) near -0.72 V on its own axis
|   falling waveform, V_fixture 5V, R_fixture 5000Ohm: 20-80 % time 95.5ns typ, 142ns min, 68.8ns max; typ from 5 V to 0.084 V
|   rising waveform, V_fixture 5V, R_fixture 5000Ohm: 20-80 % time 13.6ns typ, 15.8ns min, 11ns max; typ from 0.081 V to 5 V
[Pulldown]
|   Voltage   I(typ)   I(min)   I(max)
-4.985V   -237.9uA   -117.3uA   -299.1uA
-1.46V    -2.212mA   -1.061mA   -3.081mA
-1.115V   -7.527mA   -2.759mA   -15.68mA
-920mV    -31.59mA   -8.426mA   -50.12mA
-650mV    -29.95mA   -19.53mA   -39.61mA
1.12V     38.01mA    17.83mA    56.45mA
2.29V     55.63mA    21.98mA    98.67mA
5.23V     63.33mA    27.8mA     113.7mA
5.86V     66.83mA    58.41mA    115.2mA
6.73V     130.6mA    109.2mA    138.7mA
7.84V     224.8mA    170.4mA    269.2mA
9.985V    396.5mA    139.5mA    519.4mA
[GND Clamp]
|   Voltage   I(typ)   I(min)   I(max)
-4.985V   -3.905A    -3.962A    -3.872A
-1.235V   -232.4mA   -304.9mA   -186.9mA
-1.175V   -179.7mA   -252mA     -134.3mA
-1.13V    -141.6mA   -213.3mA   -96.81mA
-1.04V    -71.74mA   -139.6mA   -33.41mA
-995mV    -42.95mA   -105.6mA   -14.68mA
-950mV    -21.73mA   -74.6mA    -7.187mA
-905mV    -9.975mA   -48.1mA    -4.675mA
-860mV    -4.973mA   -27.86mA   -3.306mA
-770mV    -1.695mA   -7.848mA   -1.559mA
-695mV    -695.8uA   -2.725mA   -682.9uA
9.985V    0A         0A         0A
[POWER Clamp]
|   Voltage   I(typ)   I(min)   I(max)
-4.985V   -13.05nA   576.2nA    -37.29nA
-4.97V    -92.26nA   513.5nA    -99.55nA
-4.955V   -117.5nA   498.7nA    -118nA
-4.88V    -143.8nA   460.8nA    -133.4nA
-3.83V    -147.3nA   121.1nA    -133.4nA
-3.05V    -148.4nA   -18.38nA   -134nA
-1.925V   -151.1nA   -119.7nA   -136.1nA
-605mV    -155.1nA   -157.8nA   -139.4nA
190mV     -114.8nA   -126.3nA   -99.46nA
2.92V     -126.8nA   -158.5nA   -101nA
5.5V      -177.9nA   -199.9nA   -230.1nA
9.985V    -177.9nA   -199.9nA   -230.1nA
[Ramp]
R_load = 5000
|   typ   min   max
dV/dt_r   2.95111/1.33979e-08   2.6319/1.54297e-08   3.25738/1.09884e-08
dV/dt_f   2.94963/9.54096e-08   2.6219/1.41643e-07   3.25723/6.87338e-08
[Falling Waveform]
V_fixture = 5V
V_fixture_min = 4.5V
V_fixture_max = 5.5V
R_fixture = 5000Ohm
C_fixture = 0F
|   Time   V(typ)   V(min)   V(max)
0s        5V         4.502V     5.5V
126.4ns   5.049V     4.501V     5.529V
137.8ns   4.886V     4.533V     5.534V
160.9ns   4.17V      4.445V     4.512V
240.9ns   1.673V     2.891V     744.3mV
258.2ns   1.153V     2.56V      182.7mV
283.2ns   454.1mV    2.095V     101.4mV
299.1ns   205.6mV    1.802V     87.5mV
386.3ns   93.77mV    385.2mV    74.67mV
500ns     83.68mV    132.3mV    71.38mV
[Rising Waveform]
V_fixture = 5V
V_fixture_min = 4.5V
V_fixture_max = 5.5V
R_fixture = 5000Ohm
C_fixture = 0F
|   Time   V(typ)   V(min)   V(max)
0s        81.42mV    113.3mV    70.85mV
83.57ns   82.28mV    114mV      -109.1mV
86.99ns   82.31mV    114mV      2.759V
91.51ns   82.36mV    114mV      3.982V
103.5ns   -48.76mV   114.1mV    4.822V
109.8ns   3.049V     114.2mV    5.026V
122.9ns   4.228V     512.4mV    5.476V
133.2ns   4.531V     3.223V     5.477V
165.4ns   4.971V     4.467V     5.479V
500ns     5V         4.5V       5.5V
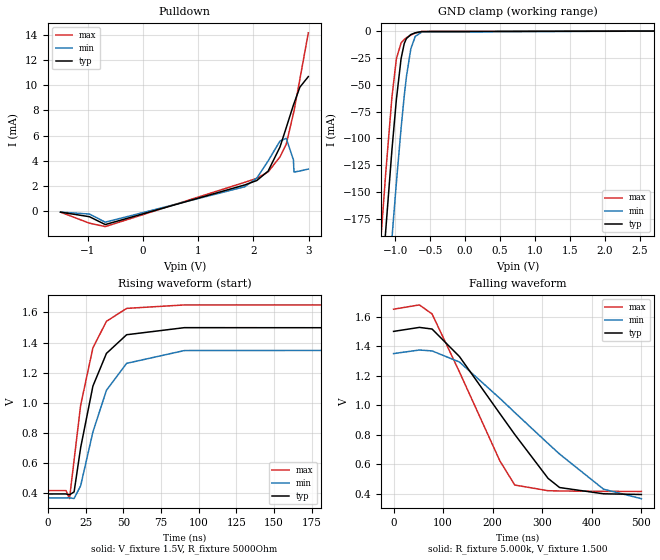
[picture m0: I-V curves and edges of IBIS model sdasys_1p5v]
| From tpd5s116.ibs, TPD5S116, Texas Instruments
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[Model]   sdasys_1p5v
Model_type   I/O_open_drain
Polarity   Non-Inverting
Enable   Active-Low
Vinl = .1107
Vinh = 1.155
Vmeas = 0.75
Vref = 1.5
Cref = 15pF
Rref = 5000
|   typ   min   max
|   (nom PVT)   (slow PVT)   (fast PVT)
C_comp   1.0804p   0.9332p   1.0809p
| Where nom  PVT is Nominal Process, 1.5V, 27C
|   Fast PVT is Strong Process,  1.65V, -40C
|   Slow PVT is Weak Process,   1.35V, 125C
[Voltage Range]   1.5   1.35   1.65
[Temperature Range]   27   125   -40
[Pullup Reference]   1.5   1.35   1.65
[Pulldown Reference]   -0   -0   -0
[Power Clamp Reference]   1.5   1.35   1.65
[GND Clamp Reference]   -0   -0   -0
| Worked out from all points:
|   slope of the pulldown table from 0 to 0.225 V, typ, clamps not added: 772 ohm
|   GND clamp passes 1 mA (typ) near -0.66 V on its own axis
|   falling waveform, R_fixture 5.000k, V_fixture 1.500: 20-80 % time 141ns typ, 190ns min, 99.9ns max; typ from 1.5 V to 0.397 V
|   rising waveform, V_fixture 1.5V, R_fixture 5000Ohm: 20-80 % time 15.5ns typ, 18.1ns min, 13.5ns max; typ from 0.394 V to 1.5 V
[Pulldown]
|   Voltage   I(typ)   I(min)   I(max)
-1.491V   -60.51uA   -55.52uA   -62.8uA
-969mV    -420.9uA   -210.9uA   -935uA
-681mV    -1.044mA   -854.7uA   -1.206mA
1.843V    2.095mA    1.954mA    2.304mA
2.064V    2.452mA    2.644mA    2.625mA
2.267V    3.194mA    4.003mA    3.13mA
2.482V    5.107mA    5.582mA    4.321mA
2.595V    6.641mA    5.794mA    5.335mA
2.725V    8.434mA    4.091mA    7.764mA
2.735V    8.552mA    3.115mA    7.957mA
2.842V    9.852mA    3.204mA    10.48mA
2.995V    10.69mA    3.356mA    14.16mA
[GND Clamp]
|   Voltage   I(typ)   I(min)   I(max)
-1.491V   -513mA     -597.5mA   -459.9mA
-1.248V   -286.1mA   -371.6mA   -232mA
-1.135V   -185.7mA   -270.6mA   -132.4mA
-1.046V   -110.5mA   -192.9mA   -61.5mA
-982.5mV  -63.74mA   -141.3mA   -25.82mA
-915mV    -25.6mA    -90.34mA   -11.02mA
-870mV    -11.63mA   -60.38mA   -7.852mA
-838.5mV  -6.975mA   -42.33mA   -6.268mA
-775.5mV  -3.27mA    -16.45mA   -3.706mA
-712.5mV  -1.683mA   -5.033mA   -1.849mA
-618mV    -485.2uA   -970uA     -419.6uA
2.995V    0A         0A         0A
[Ramp]
R_load = 5000
|   typ   min   max
dV/dt_r   0.661276/1.54842e-08   0.589036/1.81255e-08   0.739714/1.34799e-08
dV/dt_f   0.661845/1.41049e-07   0.575012/1.89995e-07   0.739478/9.98433e-08
[Falling Waveform]
R_fixture = 5.000k
V_fixture = 1.500
V_fixture_min = 1.350
V_fixture_max = 1.650
C_fixture = 0.000
|  time   V(typ)   V(min)   V(max)
0s        1.5V       1.35V      1.65V
52.09ns   1.527V     1.374V     1.679V
77.68ns   1.516V     1.368V     1.618V
132.9ns   1.33V      1.293V     1.226V
214.5ns   944mV      1.047V     624.3mV
244.5ns   803.2mV    951.8mV    460.9mV
311.8ns   505.9mV    741.5mV    422.5mV
335ns     444mV      670.5mV    420.8mV
423.6ns   401.7mV    433mV      418.1mV
500ns     396.9mV    368.5mV    417.5mV
[Rising Waveform]
V_fixture = 1.5V
V_fixture_min = 1.35V
V_fixture_max = 1.65V
R_fixture = 5000Ohm
C_fixture = 0F
|   Time   V(typ)   V(min)   V(max)
0s        394.4mV    368.5mV    416.9mV
11.88ns   394.5mV    368.5mV    416.7mV
14.16ns   388.6mV    368.6mV    362.9mV
17.23ns   408.3mV    364.2mV    620.1mV
21.57ns   702mV      448.8mV    984mV
29.71ns   1.111V     806.5mV    1.365V
38.69ns   1.328V     1.083V     1.541V
52.09ns   1.452V     1.262V     1.627V
90.46ns   1.499V     1.347V     1.65V
500ns     1.497V     1.35V      1.65V
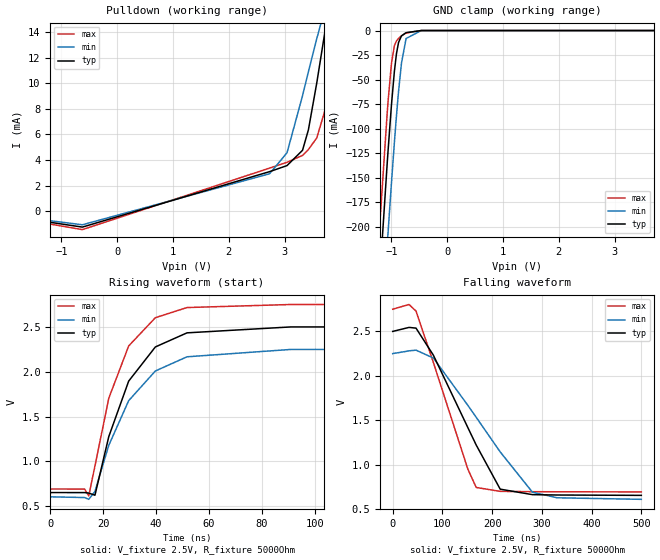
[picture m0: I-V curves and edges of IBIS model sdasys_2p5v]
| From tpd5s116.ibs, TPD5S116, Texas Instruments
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[Model]   sdasys_2p5v
Model_type   I/O_open_drain
Polarity   Non-Inverting
Enable   Active-Low
Vinl = .1845
Vinh = 1.925
Vmeas = 1.25
Vref = 2.5
Cref = 15pF
Rref = 5000
|   typ   min   max
|   (nom PVT)   (slow PVT)   (fast PVT)
C_comp   1.0804p   0.9332p   1.0809p
| Where nom  PVT is Nominal Process, 2.5V, 27C
|   Fast PVT is Strong Process,  2.75V, -40C
|   Slow PVT is Weak Process,   2.25V, 125C
[Voltage Range]   2.5   2.25   2.75
[Temperature Range]   27   125   -40
[Pullup Reference]   2.5   2.25   2.75
[Pulldown Reference]   -0   -0   -0
[Power Clamp Reference]   2.5   2.25   2.75
[GND Clamp Reference]   -0   -0   -0
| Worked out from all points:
|   slope of the pulldown table from 0 to 0.375 V, typ, clamps not added: 761 ohm
|   GND clamp passes 1 mA (typ) near -0.66 V on its own axis
|   falling waveform, V_fixture 2.5V, R_fixture 5000Ohm: 20-80 % time 94.5ns typ, 123ns min, 71ns max; typ from 2.5 V to 0.654 V
|   rising waveform, V_fixture 2.5V, R_fixture 5000Ohm: 20-80 % time 14.7ns typ, 16.7ns min, 12.9ns max; typ from 0.653 V to 2.5 V
[Pulldown]
|   Voltage   I(typ)   I(min)   I(max)
-2.485V   -25.62uA   -26.71uA   -24.18uA
-625mV    -1.227mA   -1.046mA   -1.425mA
2.728V    3.096mA    2.931mA    3.371mA
3.042V    3.57mA     4.571mA    3.83mA
3.32V     4.765mA    9.023mA    4.364mA
3.425V    6.356mA    10.89mA    4.822mA
3.575V    10.02mA    13.47mA    5.726mA
3.74V     14.52mA    16.1mA     8.143mA
3.987V    21.35mA    20mA       17.78mA
4.565V    35.34mA    21.67mA    40.99mA
4.79V     39.84mA    8.299mA    49.3mA
4.992V    42.54mA    7.391mA    56.35mA
[GND Clamp]
|   Voltage   I(typ)   I(min)   I(max)
-2.485V   -1.478A    -1.557A    -1.43A
-1.225V   -265.2mA   -350.7mA   -211.1mA
-1.075V   -134.4mA   -218mA     -83.16mA
-1.06V    -122.1mA   -205.2mA   -71.89mA
-1V       -75.97mA   -155.4mA   -33.75mA
-947.5mV  -41.8mA    -114.2mA   -15.53mA
-910mV    -23.55mA   -86.82mA   -10.56mA
-872.5mV  -12.15mA   -61.93mA   -7.991mA
-820mV    -5.411mA   -33.18mA   -5.442mA
-737.5mV  -2.207mA   -8.138mA   -2.498mA
-467.5mV  -30.24uA   -89.47uA   -14.49uA
4.992V    0A         0A         0A
[Ramp]
R_load = 5000
|   typ   min   max
dV/dt_r   1.10666/1.46622e-08   0.986342/1.66837e-08   1.2328/1.29473e-08
dV/dt_f   1.10767/9.44441e-08   0.984456/1.22907e-07   1.23442/7.09901e-08
[Falling Waveform]
V_fixture = 2.5V
V_fixture_min = 2.25V
V_fixture_max = 2.75V
R_fixture = 5000Ohm
C_fixture = 0F
|   Time   V(typ)   V(min)   V(max)
0s        2.5V       2.25V      2.75V
32.81ns   2.545V     2.281V     2.803V
46.87ns   2.537V     2.289V     2.729V
81.8ns    2.232V     2.2V       2.15V
151.2ns   1.416V     1.667V     947.4mV
168ns     1.22V      1.532V     742.7mV
216.2ns   723.6mV    1.143V     698.9mV
281ns     662mV      689.5mV    695.3mV
330.9ns   657.8mV    626.5mV    694.3mV
500ns     653.9mV    609.2mV    692.6mV
[Rising Waveform]
V_fixture = 2.5V
V_fixture_min = 2.25V
V_fixture_max = 2.75V
R_fixture = 5000Ohm
C_fixture = 0F
|   Time   V(typ)   V(min)   V(max)
0s        653.5mV    606.1mV    693mV
12.99ns   653.4mV    598.1mV    692.9mV
14.56ns   647.9mV    578.2mV    616.9mV
16.9ns    624mV      666.4mV    949.8mV
22.14ns   1.278V     1.181V     1.706V
29.66ns   1.896V     1.678V     2.288V
39.76ns   2.277V     2.009V     2.603V
51.73ns   2.434V     2.167V     2.716V
90.95ns   2.5V       2.249V     2.75V
500ns     2.498V     2.25V      2.748V
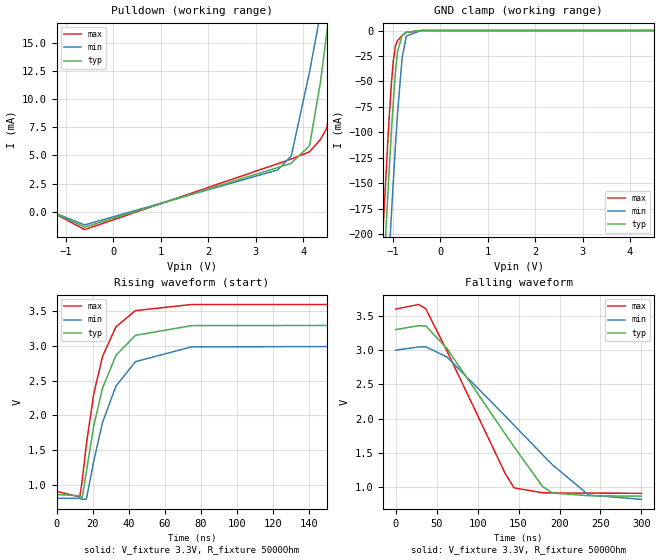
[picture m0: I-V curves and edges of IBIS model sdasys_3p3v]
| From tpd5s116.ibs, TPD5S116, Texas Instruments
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[Model]   sdasys_3p3v
Model_type   I/O_open_drain
Polarity   Non-Inverting
Enable   Active-Low
Vinl = .246
Vinh = 2.52
Vmeas = 1.65
Vref = 3.3
Cref = 15pF
Rref = 5000
|   typ   min   max
|   (nom PVT)   (slow PVT)   (fast PVT)
C_comp   1.0804p   0.9332p   1.0809p
| Where nom  PVT is Nominal Process, 3.3V, 27C
|   Fast PVT is Strong Process,  3.6V, -40C
|   Slow PVT is Weak Process,   3.0V, 125C
[Voltage Range]   3.3   3   3.6
[Temperature Range]   27   125   -40
[Pullup Reference]   3.3   3   3.6
[Pulldown Reference]   -0   -0   -0
[Power Clamp Reference]   3.3   3   3.6
[GND Clamp Reference]   -0   -0   -0
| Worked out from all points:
|   slope of the pulldown table from 0 to 0.495 V, typ, clamps not added: 758 ohm
|   GND clamp passes 1 mA (typ) near -0.67 V on its own axis
|   falling waveform, V_fixture 3.3V, R_fixture 5000Ohm: 20-80 % time 83.3ns typ, 106ns min, 63.9ns max; typ from 3.3 V to 0.865 V
|   rising waveform, V_fixture 3.3V, R_fixture 5000Ohm: 20-80 % time 14.4ns typ, 16.1ns min, 12.5ns max; typ from 0.862 V to 3.3 V
[Pulldown]
|   Voltage   I(typ)   I(min)   I(max)
-3.28V    -18.8uA    -20.19uA   -17.43uA
-1.241V   -142.1uA   -118.8uA   -166.3uA
-607.2mV  -1.378mA   -1.184mA   -1.601mA
3.462V    3.919mA    3.71mA     4.264mA
3.749V    4.309mA    4.948mA    4.684mA
4.135V    5.867mA    12.45mA    5.331mA
4.363V    11.49mA    17.61mA    6.42mA
4.501V    15.99mA    20.78mA    7.454mA
4.679V    21.98mA    24.77mA    13.13mA
5.174V    38.54mA    34.41mA    37.26mA
6.382V    69.83mA    18.41mA    89.55mA
6.59V     72.37mA    13.75mA    97.19mA
[GND Clamp]
|   Voltage   I(typ)   I(min)   I(max)
-3.28V    -2.262A    -2.338A    -2.216A
-1.211V   -252.6mA   -338.2mA   -198.6mA
-1.102V   -157.1mA   -241.5mA   -104.7mA
-1.082V   -140.5mA   -224.4mA   -88.89mA
-1.033V   -100.6mA   -182.4mA   -52.99mA
-993.3mV  -71.2mA    -150mA     -30.49mA
-943.8mV  -39.73mA   -111.4mA   -14.83mA
-904.2mV  -21.32mA   -82.78mA   -10.08mA
-805.2mV  -4.518mA   -26.75mA   -4.827mA
-716.1mV  -1.752mA   -5.392mA   -1.935mA
-409.2mV  -7.87uA    -32.5uA    -2.538uA
6.59V     0A         0A         0A
[Ramp]
R_load = 5000
|   typ   min   max
dV/dt_r   1.46273/1.44079e-08   1.31625/1.61342e-08   1.61488/1.25489e-08
dV/dt_f   1.46091/8.32385e-08   1.30827/1.05801e-07   1.61549/6.38427e-08
[Falling Waveform]
V_fixture = 3.3V
V_fixture_min = 3V
V_fixture_max = 3.6V
R_fixture = 5000Ohm
C_fixture = 0F
|   Time   V(typ)   V(min)   V(max)
0s        3.3V       3V         3.6V
27.9ns    3.357V     3.046V     3.667V
36.66ns   3.354V     3.05V      3.606V
62.86ns   3.019V     2.898V     2.981V
133.2ns   1.784V     2.043V     1.209V
144.4ns   1.589V     1.904V     986.9mV
179.3ns   1.006V     1.471V     915.7mV
191.3ns   911.2mV    1.325V     913.6mV
235.7ns   872mV      881.5mV    909.8mV
300ns     865.2mV    819.5mV    907.5mV
[Rising Waveform]
V_fixture = 3.3V
V_fixture_min = 3V
V_fixture_max = 3.6V
R_fixture = 5000Ohm
C_fixture = 0F
|   Time   V(typ)   V(min)   V(max)
0s        861.7mV    806mV      906.8mV
12.82ns   842.4mV    805.9mV    825.9mV
14.24ns   818.3mV    791.4mV    1.065V
16.54ns   1.191V     794.5mV    1.588V
20.64ns   1.856V     1.345V     2.313V
25.49ns   2.395V     1.9V       2.851V
32.91ns   2.866V     2.423V     3.277V
43.68ns   3.154V     2.775V     3.511V
74.86ns   3.295V     2.989V     3.599V
300ns     3.3V       3V         3.598V
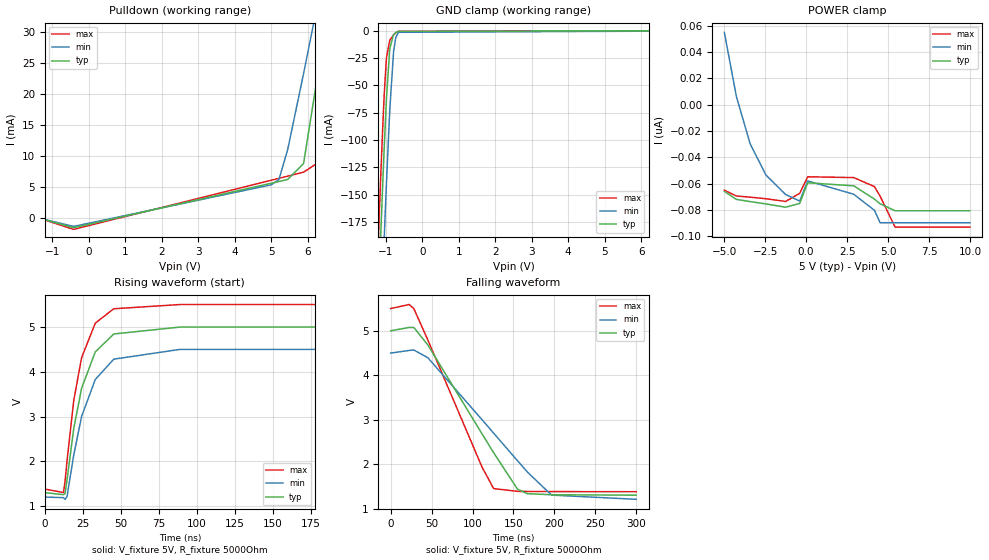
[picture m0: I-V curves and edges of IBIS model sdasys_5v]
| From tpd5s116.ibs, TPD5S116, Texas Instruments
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[Model]   sdasys_5v
Model_type   I/O_open_drain
Polarity   Non-Inverting
Enable   Active-Low
Vinl = .369
Vinh = 3.85
Vmeas = 2.5
Vref = 5
Cref = 15pF
Rref = 5000
|   typ   min   max
|   (nom PVT)   (slow PVT)   (fast PVT)
C_comp   1.0804p   0.9332p   1.0809p
| Where nom  PVT is Nominal Process, 5V, 27C
|   Fast PVT is Strong Process,  5.5V, -40C
|   Slow PVT is Weak Process,   4.5V, 125C
[Voltage Range]   5   4.5   5.5
[Temperature Range]   27   125   -40
[Pullup Reference]   5   4.5   5.5
[Pulldown Reference]   -0   -0   -0
[Power Clamp Reference]   5   4.5   5.5
[GND Clamp Reference]   -0   -0   -0
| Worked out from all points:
|   slope of the pulldown table from 0 to 0.75 V, typ, clamps not added: 756 ohm
|   GND clamp passes 1 mA (typ) near -0.67 V on its own axis
|   falling waveform, V_fixture 5V, R_fixture 5000Ohm: 20-80 % time 73.5ns typ, 92.6ns min, 57.2ns max; typ from 5 V to 1.31 V
|   rising waveform, V_fixture 5V, R_fixture 5000Ohm: 20-80 % time 14.1ns typ, 15.7ns min, 12.2ns max; typ from 1.3 V to 5 V
[Pulldown]
|   Voltage   I(typ)   I(min)   I(max)
-4.985V   -13.15uA   -14.36uA   -12.15uA
-1.25V    -168.4uA   -141.5uA   -197.5uA
-410mV    -1.526mA   -1.318mA   -1.795mA
5.005V    5.641mA    5.389mA    6.119mA
5.215V    5.92mA     6.246mA    6.428mA
5.455V    6.258mA    11.07mA    6.78mA
5.89V     8.828mA    23.33mA    7.425mA
6.25V     22.11mA    33.87mA    8.799mA
6.445V    30.2mA     39.56mA    10.66mA
6.565V    35.21mA    43.02mA    15.71mA
6.895V    48.95mA    52.19mA    34.83mA
9.985V    142.3mA    38.16mA    191.8mA
[GND Clamp]
|   Voltage   I(typ)   I(min)   I(max)
-4.985V   -3.951A    -4.023A    -3.908A
-1.25V    -287.9mA   -373.5mA   -233.8mA
-1.16V    -207.1mA   -292.3mA   -153.4mA
-1.13V    -180.9mA   -265.8mA   -127.7mA
-1.07V    -130.3mA   -213.7mA   -79.35mA
-1.04V    -106.2mA   -188.3mA   -57.72mA
-980mV    -62.05mA   -139.4mA   -24.84mA
-890mV    -16.6mA    -73.18mA   -9.051mA
-785mV    -3.613mA   -19.36mA   -4.048mA
-725mV    -1.931mA   -6.398mA   -2.159mA
-650mV    -773uA     -1.632mA   -737.3uA
9.985V    0A         0A         0A
[POWER Clamp]
|   Voltage   I(typ)   I(min)   I(max)
-4.985V   -65.81nA   55.03nA    -64.92nA
-4.25V    -71.9nA    6.253nA    -69.31nA
-3.41V    -73.55nA   -29.69nA   -70.19nA
-2.45V    -75.32nA   -53.4nA    -71.39nA
-1.25V    -77.83nA   -68.17nA   -73.43nA
-395mV    -74.97nA   -73.12nA   -67.34nA
100mV     -59.25nA   -57.83nA   -54.7nA
2.905V    -61.58nA   -67.99nA   -55.32nA
4.165V    -71.64nA   -80.14nA   -62.16nA
4.51V     -75.22nA   -89.61nA   -69.42nA
5.425V    -80.53nA   -89.61nA   -92.97nA
9.985V    -80.53nA   -89.61nA   -92.91nA
[Ramp]
R_load = 5000
|   typ   min   max
dV/dt_r   2.21688/1.4124e-08   1.97569/1.57208e-08   2.46771/1.22475e-08
dV/dt_f   2.2161/7.34707e-08   1.97146/9.25741e-08   2.46891/5.71204e-08
[Falling Waveform]
V_fixture = 5V
V_fixture_min = 4.5V
V_fixture_max = 5.5V
R_fixture = 5000Ohm
C_fixture = 0F
|   Time   V(typ)   V(min)   V(max)
0s        5V         4.5V       5.5V
22.5ns    5.075V     4.559V     5.591V
28.26ns   5.074V     4.569V     5.5V
45.39ns   4.681V     4.395V     4.793V
111.6ns   2.685V     3.003V     1.938V
125.8ns   2.26V      2.7V       1.455V
155ns     1.441V     2.08V      1.393V
167ns     1.341V     1.827V     1.391V
196.5ns   1.317V     1.309V     1.388V
300ns     1.307V     1.214V     1.385V
[Rising Waveform]
V_fixture = 5V
V_fixture_min = 4.5V
V_fixture_max = 5.5V
R_fixture = 5000Ohm
C_fixture = 0F
|   Time   V(typ)   V(min)   V(max)
0s        1.305V     1.207V     1.385V
12.29ns   1.26V      1.193V     1.307V
13.35ns   1.284V     1.156V     1.564V
14.62ns   1.587V     1.218V     2.011V
19ns      2.726V     2.138V     3.348V
24.19ns   3.63V      3.002V     4.31V
33.17ns   4.44V      3.826V     5.082V
45.35ns   4.841V     4.28V      5.403V
88.76ns   4.995V     4.497V     5.497V
300ns     4.999V     4.5V       5.498V
